VERSION 5.8 ;
BUSBITCHARS "[]" ;
DIVIDERCHAR "/" ;
UNITS
    DATABASE MICRONS 1000 ;
END UNITS

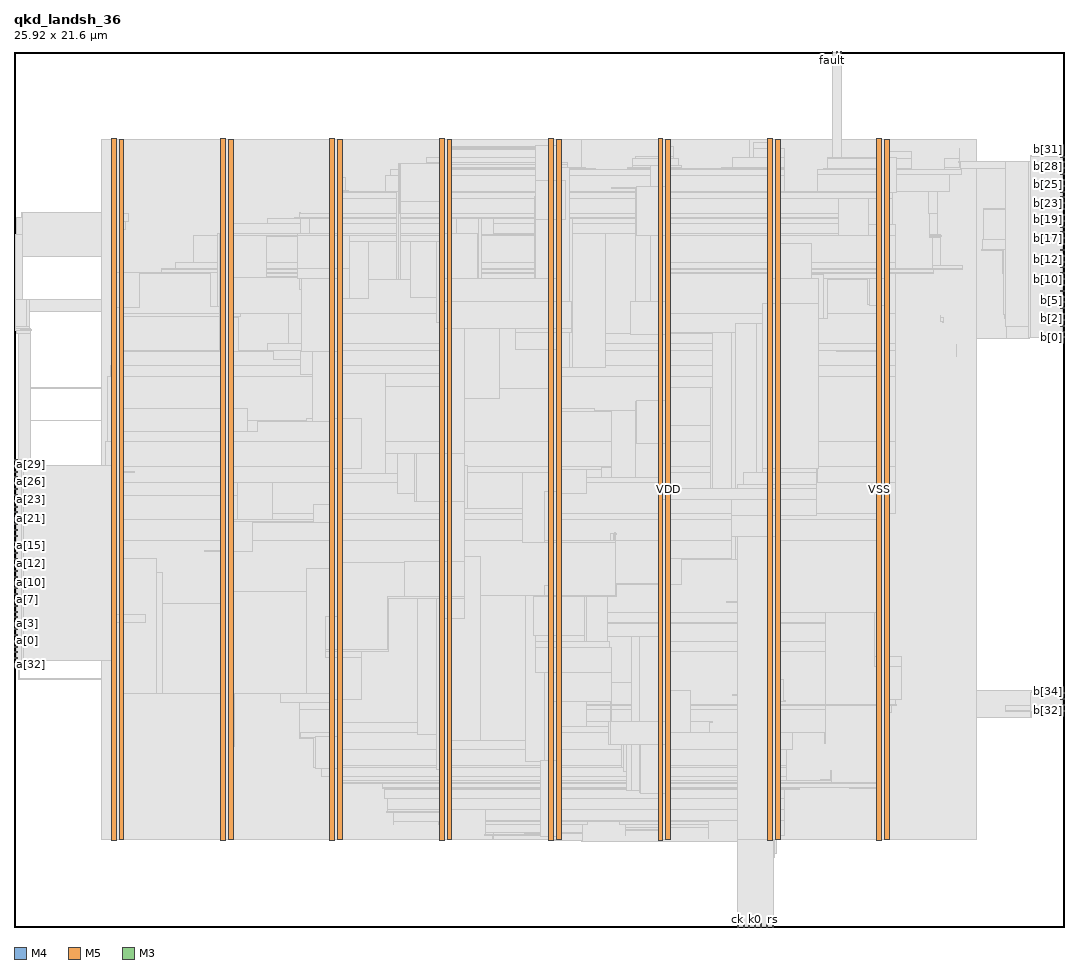
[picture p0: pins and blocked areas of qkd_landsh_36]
MACRO qkd_landsh_36
  FOREIGN qkd_landsh_36 0 0 ;
  CLASS BLOCK ;
  SIZE 25.92 BY 21.6 ;
  PIN a[0]
    DIRECTION INPUT ;
    USE SIGNAL ;
    PORT
      LAYER M4 ;
        RECT  0 7.056 0.084 7.08 ;
    END
  END a[0]
  PIN a[10]
    DIRECTION INPUT ;
    USE SIGNAL ;
    PORT
      LAYER M4 ;
        RECT  0 8.496 0.084 8.52 ;
    END
  END a[10]
  PIN a[11]
    DIRECTION INPUT ;
    USE SIGNAL ;
    PORT
      LAYER M4 ;
        RECT  0 8.64 0.084 8.664 ;
    END
  END a[11]
  PIN a[12]
    DIRECTION INPUT ;
    USE SIGNAL ;
    PORT
      LAYER M4 ;
        RECT  0 8.784 0.084 8.808 ;
    END
  END a[12]
  PIN a[13]
    DIRECTION INPUT ;
    USE SIGNAL ;
    PORT
      LAYER M4 ;
        RECT  0 8.928 0.084 8.952 ;
    END
  END a[13]
  PIN a[14]
    DIRECTION INPUT ;
    USE SIGNAL ;
    PORT
      LAYER M4 ;
        RECT  0 9.072 0.084 9.096 ;
    END
  END a[14]
  PIN a[15]
    DIRECTION INPUT ;
    USE SIGNAL ;
    PORT
      LAYER M4 ;
        RECT  0 9.216 0.084 9.24 ;
    END
  END a[15]
  PIN a[16]
    DIRECTION INPUT ;
    USE SIGNAL ;
    PORT
      LAYER M4 ;
        RECT  0 9.36 0.084 9.384 ;
    END
  END a[16]
  PIN a[17]
    DIRECTION INPUT ;
    USE SIGNAL ;
    PORT
      LAYER M4 ;
        RECT  0 9.504 0.084 9.528 ;
    END
  END a[17]
  PIN a[18]
    DIRECTION INPUT ;
    USE SIGNAL ;
    PORT
      LAYER M4 ;
        RECT  0 9.648 0.084 9.672 ;
    END
  END a[18]
  PIN a[19]
    DIRECTION INPUT ;
    USE SIGNAL ;
    PORT
      LAYER M4 ;
        RECT  0 9.792 0.084 9.816 ;
    END
  END a[19]
  PIN a[1]
    DIRECTION INPUT ;
    USE SIGNAL ;
    PORT
      LAYER M4 ;
        RECT  0 7.2 0.084 7.224 ;
    END
  END a[1]
  PIN a[20]
    DIRECTION INPUT ;
    USE SIGNAL ;
    PORT
      LAYER M4 ;
        RECT  0 9.936 0.084 9.96 ;
    END
  END a[20]
  PIN a[21]
    DIRECTION INPUT ;
    USE SIGNAL ;
    PORT
      LAYER M4 ;
        RECT  0 10.08 0.084 10.104 ;
    END
  END a[21]
  PIN a[22]
    DIRECTION INPUT ;
    USE SIGNAL ;
    PORT
      LAYER M4 ;
        RECT  0 10.224 0.084 10.248 ;
    END
  END a[22]
  PIN a[23]
    DIRECTION INPUT ;
    USE SIGNAL ;
    PORT
      LAYER M4 ;
        RECT  0 10.368 0.084 10.392 ;
    END
  END a[23]
  PIN a[24]
    DIRECTION INPUT ;
    USE SIGNAL ;
    PORT
      LAYER M4 ;
        RECT  0 10.512 0.084 10.536 ;
    END
  END a[24]
  PIN a[25]
    DIRECTION INPUT ;
    USE SIGNAL ;
    PORT
      LAYER M4 ;
        RECT  0 10.656 0.084 10.68 ;
    END
  END a[25]
  PIN a[26]
    DIRECTION INPUT ;
    USE SIGNAL ;
    PORT
      LAYER M4 ;
        RECT  0 10.8 0.084 10.824 ;
    END
  END a[26]
  PIN a[27]
    DIRECTION INPUT ;
    USE SIGNAL ;
    PORT
      LAYER M4 ;
        RECT  0 10.944 0.084 10.968 ;
    END
  END a[27]
  PIN a[28]
    DIRECTION INPUT ;
    USE SIGNAL ;
    PORT
      LAYER M4 ;
        RECT  0 11.088 0.084 11.112 ;
    END
  END a[28]
  PIN a[29]
    DIRECTION INPUT ;
    USE SIGNAL ;
    PORT
      LAYER M4 ;
        RECT  0 11.232 0.084 11.256 ;
    END
  END a[29]
  PIN a[2]
    DIRECTION INPUT ;
    USE SIGNAL ;
    PORT
      LAYER M4 ;
        RECT  0 7.344 0.084 7.368 ;
    END
  END a[2]
  PIN a[30]
    DIRECTION INPUT ;
    USE SIGNAL ;
    PORT
      LAYER M4 ;
        RECT  0 11.376 0.084 11.4 ;
    END
  END a[30]
  PIN a[31]
    DIRECTION INPUT ;
    USE SIGNAL ;
    PORT
      LAYER M4 ;
        RECT  0 11.52 0.084 11.544 ;
    END
  END a[31]
  PIN a[32]
    DIRECTION INPUT ;
    USE SIGNAL ;
    PORT
      LAYER M4 ;
        RECT  0 6.48 0.084 6.504 ;
    END
  END a[32]
  PIN a[33]
    DIRECTION INPUT ;
    USE SIGNAL ;
    PORT
      LAYER M4 ;
        RECT  0 6.624 0.084 6.648 ;
    END
  END a[33]
  PIN a[34]
    DIRECTION INPUT ;
    USE SIGNAL ;
    PORT
      LAYER M4 ;
        RECT  0 6.768 0.084 6.792 ;
    END
  END a[34]
  PIN a[35]
    DIRECTION INPUT ;
    USE SIGNAL ;
    PORT
      LAYER M4 ;
        RECT  0 6.912 0.084 6.936 ;
    END
  END a[35]
  PIN a[3]
    DIRECTION INPUT ;
    USE SIGNAL ;
    PORT
      LAYER M4 ;
        RECT  0 7.488 0.084 7.512 ;
    END
  END a[3]
  PIN a[4]
    DIRECTION INPUT ;
    USE SIGNAL ;
    PORT
      LAYER M4 ;
        RECT  0 7.632 0.084 7.656 ;
    END
  END a[4]
  PIN a[5]
    DIRECTION INPUT ;
    USE SIGNAL ;
    PORT
      LAYER M4 ;
        RECT  0 7.776 0.084 7.8 ;
    END
  END a[5]
  PIN a[6]
    DIRECTION INPUT ;
    USE SIGNAL ;
    PORT
      LAYER M4 ;
        RECT  0 7.92 0.084 7.944 ;
    END
  END a[6]
  PIN a[7]
    DIRECTION INPUT ;
    USE SIGNAL ;
    PORT
      LAYER M4 ;
        RECT  0 8.064 0.084 8.088 ;
    END
  END a[7]
  PIN a[8]
    DIRECTION INPUT ;
    USE SIGNAL ;
    PORT
      LAYER M4 ;
        RECT  0 8.208 0.084 8.232 ;
    END
  END a[8]
  PIN a[9]
    DIRECTION INPUT ;
    USE SIGNAL ;
    PORT
      LAYER M4 ;
        RECT  0 8.352 0.084 8.376 ;
    END
  END a[9]
  PIN b[0]
    DIRECTION OUTPUT ;
    USE SIGNAL ;
    PORT
      LAYER M4 ;
        RECT  25.836 14.544 25.92 14.568 ;
    END
  END b[0]
  PIN b[10]
    DIRECTION OUTPUT ;
    USE SIGNAL ;
    PORT
      LAYER M4 ;
        RECT  25.836 15.984 25.92 16.008 ;
    END
  END b[10]
  PIN b[11]
    DIRECTION OUTPUT ;
    USE SIGNAL ;
    PORT
      LAYER M4 ;
        RECT  25.836 16.128 25.92 16.152 ;
    END
  END b[11]
  PIN b[12]
    DIRECTION OUTPUT ;
    USE SIGNAL ;
    PORT
      LAYER M4 ;
        RECT  25.836 16.272 25.92 16.296 ;
    END
  END b[12]
  PIN b[13]
    DIRECTION OUTPUT ;
    USE SIGNAL ;
    PORT
      LAYER M4 ;
        RECT  25.836 16.416 25.92 16.44 ;
    END
  END b[13]
  PIN b[14]
    DIRECTION OUTPUT ;
    USE SIGNAL ;
    PORT
      LAYER M4 ;
        RECT  25.836 16.56 25.92 16.584 ;
    END
  END b[14]
  PIN b[15]
    DIRECTION OUTPUT ;
    USE SIGNAL ;
    PORT
      LAYER M4 ;
        RECT  25.836 16.704 25.92 16.728 ;
    END
  END b[15]
  PIN b[16]
    DIRECTION OUTPUT ;
    USE SIGNAL ;
    PORT
      LAYER M4 ;
        RECT  25.836 16.848 25.92 16.872 ;
    END
  END b[16]
  PIN b[17]
    DIRECTION OUTPUT ;
    USE SIGNAL ;
    PORT
      LAYER M4 ;
        RECT  25.836 16.992 25.92 17.016 ;
    END
  END b[17]
  PIN b[18]
    DIRECTION OUTPUT ;
    USE SIGNAL ;
    PORT
      LAYER M4 ;
        RECT  25.836 17.136 25.92 17.16 ;
    END
  END b[18]
  PIN b[19]
    DIRECTION OUTPUT ;
    USE SIGNAL ;
    PORT
      LAYER M4 ;
        RECT  25.836 17.28 25.92 17.304 ;
    END
  END b[19]
  PIN b[1]
    DIRECTION OUTPUT ;
    USE SIGNAL ;
    PORT
      LAYER M4 ;
        RECT  25.836 14.688 25.92 14.712 ;
    END
  END b[1]
  PIN b[20]
    DIRECTION OUTPUT ;
    USE SIGNAL ;
    PORT
      LAYER M4 ;
        RECT  25.836 17.424 25.92 17.448 ;
    END
  END b[20]
  PIN b[21]
    DIRECTION OUTPUT ;
    USE SIGNAL ;
    PORT
      LAYER M4 ;
        RECT  25.836 17.568 25.92 17.592 ;
    END
  END b[21]
  PIN b[22]
    DIRECTION OUTPUT ;
    USE SIGNAL ;
    PORT
      LAYER M4 ;
        RECT  25.836 17.712 25.92 17.736 ;
    END
  END b[22]
  PIN b[23]
    DIRECTION OUTPUT ;
    USE SIGNAL ;
    PORT
      LAYER M4 ;
        RECT  25.836 17.856 25.92 17.88 ;
    END
  END b[23]
  PIN b[24]
    DIRECTION OUTPUT ;
    USE SIGNAL ;
    PORT
      LAYER M4 ;
        RECT  25.836 18 25.92 18.024 ;
    END
  END b[24]
  PIN b[25]
    DIRECTION OUTPUT ;
    USE SIGNAL ;
    PORT
      LAYER M4 ;
        RECT  25.836 18.144 25.92 18.168 ;
    END
  END b[25]
  PIN b[26]
    DIRECTION OUTPUT ;
    USE SIGNAL ;
    PORT
      LAYER M4 ;
        RECT  25.836 18.288 25.92 18.312 ;
    END
  END b[26]
  PIN b[27]
    DIRECTION OUTPUT ;
    USE SIGNAL ;
    PORT
      LAYER M4 ;
        RECT  25.836 18.432 25.92 18.456 ;
    END
  END b[27]
  PIN b[28]
    DIRECTION OUTPUT ;
    USE SIGNAL ;
    PORT
      LAYER M4 ;
        RECT  25.836 18.576 25.92 18.6 ;
    END
  END b[28]
  PIN b[29]
    DIRECTION OUTPUT ;
    USE SIGNAL ;
    PORT
      LAYER M4 ;
        RECT  25.836 18.72 25.92 18.744 ;
    END
  END b[29]
  PIN b[2]
    DIRECTION OUTPUT ;
    USE SIGNAL ;
    PORT
      LAYER M4 ;
        RECT  25.836 14.832 25.92 14.856 ;
    END
  END b[2]
  PIN b[30]
    DIRECTION OUTPUT ;
    USE SIGNAL ;
    PORT
      LAYER M4 ;
        RECT  25.836 18.864 25.92 18.888 ;
    END
  END b[30]
  PIN b[31]
    DIRECTION OUTPUT ;
    USE SIGNAL ;
    PORT
      LAYER M4 ;
        RECT  25.836 19.008 25.92 19.032 ;
    END
  END b[31]
  PIN b[32]
    DIRECTION OUTPUT ;
    USE SIGNAL ;
    PORT
      LAYER M4 ;
        RECT  25.836 5.328 25.92 5.352 ;
    END
  END b[32]
  PIN b[33]
    DIRECTION OUTPUT ;
    USE SIGNAL ;
    PORT
      LAYER M4 ;
        RECT  25.836 5.472 25.92 5.496 ;
    END
  END b[33]
  PIN b[34]
    DIRECTION OUTPUT ;
    USE SIGNAL ;
    PORT
      LAYER M4 ;
        RECT  25.836 5.616 25.92 5.64 ;
    END
  END b[34]
  PIN b[35]
    DIRECTION OUTPUT ;
    USE SIGNAL ;
    PORT
      LAYER M4 ;
        RECT  25.836 5.76 25.92 5.784 ;
    END
  END b[35]
  PIN b[3]
    DIRECTION OUTPUT ;
    USE SIGNAL ;
    PORT
      LAYER M4 ;
        RECT  25.836 14.976 25.92 15 ;
    END
  END b[3]
  PIN b[4]
    DIRECTION OUTPUT ;
    USE SIGNAL ;
    PORT
      LAYER M4 ;
        RECT  25.836 15.12 25.92 15.144 ;
    END
  END b[4]
  PIN b[5]
    DIRECTION OUTPUT ;
    USE SIGNAL ;
    PORT
      LAYER M4 ;
        RECT  25.836 15.264 25.92 15.288 ;
    END
  END b[5]
  PIN b[6]
    DIRECTION OUTPUT ;
    USE SIGNAL ;
    PORT
      LAYER M4 ;
        RECT  25.836 15.408 25.92 15.432 ;
    END
  END b[6]
  PIN b[7]
    DIRECTION OUTPUT ;
    USE SIGNAL ;
    PORT
      LAYER M4 ;
        RECT  25.836 15.552 25.92 15.576 ;
    END
  END b[7]
  PIN b[8]
    DIRECTION OUTPUT ;
    USE SIGNAL ;
    PORT
      LAYER M4 ;
        RECT  25.836 15.696 25.92 15.72 ;
    END
  END b[8]
  PIN b[9]
    DIRECTION OUTPUT ;
    USE SIGNAL ;
    PORT
      LAYER M4 ;
        RECT  25.836 15.84 25.92 15.864 ;
    END
  END b[9]
  PIN ck
    DIRECTION INPUT ;
    USE SIGNAL ;
    PORT
      LAYER M5 ;
        RECT  17.856 0 17.88 0.084 ;
    END
  END ck
  PIN ckf
    DIRECTION INPUT ;
    USE SIGNAL ;
    PORT
      LAYER M5 ;
        RECT  18 0 18.024 0.084 ;
    END
  END ckf
  PIN ea
    DIRECTION INPUT ;
    USE SIGNAL ;
    PORT
      LAYER M5 ;
        RECT  18.144 0 18.168 0.084 ;
    END
  END ea
  PIN fault
    DIRECTION OUTPUT ;
    USE SIGNAL ;
    PORT
      LAYER M3 ;
        RECT  20.196 21.563 20.214 21.6 ;
    END
  END fault
  PIN k0
    DIRECTION INPUT ;
    USE SIGNAL ;
    PORT
      LAYER M5 ;
        RECT  18.288 0 18.312 0.084 ;
    END
  END k0
  PIN k1
    DIRECTION INPUT ;
    USE SIGNAL ;
    PORT
      LAYER M5 ;
        RECT  18.432 0 18.456 0.084 ;
    END
  END k1
  PIN k2
    DIRECTION INPUT ;
    USE SIGNAL ;
    PORT
      LAYER M5 ;
        RECT  18.576 0 18.6 0.084 ;
    END
  END k2
  PIN rs
    DIRECTION INPUT ;
    USE SIGNAL ;
    PORT
      LAYER M5 ;
        RECT  18.72 0 18.744 0.084 ;
    END
  END rs
  PIN tie_hi
    DIRECTION OUTPUT ;
    USE SIGNAL ;
    PORT
      LAYER M3 ;
        RECT  20.304 21.563 20.322 21.6 ;
    END
  END tie_hi
  PIN tie_lo
    DIRECTION OUTPUT ;
    USE SIGNAL ;
    PORT
      LAYER M3 ;
        RECT  20.412 21.563 20.43 21.6 ;
    END
  END tie_lo
  PIN VDD
    DIRECTION INOUT ;
    USE POWER ;
    PORT
      LAYER M5 ;
        RECT  21.492 2.151 21.612 19.449 ;
        RECT  18.792 2.151 18.912 19.449 ;
        RECT  16.092 2.151 16.212 19.449 ;
        RECT  13.392 2.151 13.512 19.449 ;
        RECT  10.692 2.151 10.812 19.449 ;
        RECT  7.992 2.151 8.112 19.449 ;
        RECT  5.292 2.151 5.412 19.449 ;
        RECT  2.592 2.151 2.712 19.449 ;
    END
  END VDD
  PIN VSS
    DIRECTION INOUT ;
    USE GROUND ;
    PORT
      LAYER M5 ;
        RECT  21.3 2.137 21.42 19.463 ;
        RECT  18.6 2.137 18.72 19.463 ;
        RECT  15.9 2.137 16.02 19.463 ;
        RECT  13.2 2.137 13.32 19.463 ;
        RECT  10.5 2.137 10.62 19.463 ;
        RECT  7.8 2.137 7.92 19.463 ;
        RECT  5.1 2.137 5.22 19.463 ;
        RECT  2.4 2.137 2.52 19.463 ;
    END
  END VSS
  OBS
    LAYER RVTN ;
     RECT  2.16 2.16 23.76 2.295 ;
     RECT  2.16 2.565 23.76 2.835 ;
     RECT  2.16 3.105 23.76 3.375 ;
     RECT  2.16 3.645 23.76 3.915 ;
     RECT  2.16 4.185 23.76 4.455 ;
     RECT  2.16 4.725 23.76 4.995 ;
     RECT  2.16 5.265 23.76 5.535 ;
     RECT  2.16 5.805 23.76 6.075 ;
     RECT  2.16 6.345 23.76 6.615 ;
     RECT  2.16 6.885 23.76 7.155 ;
     RECT  2.16 7.425 23.76 7.695 ;
     RECT  2.16 7.965 23.76 8.235 ;
     RECT  2.16 8.505 23.76 8.775 ;
     RECT  2.16 9.045 23.76 9.315 ;
     RECT  2.16 9.585 23.76 9.855 ;
     RECT  2.16 10.125 23.76 10.395 ;
     RECT  2.16 10.665 23.76 10.935 ;
     RECT  2.16 11.205 23.76 11.475 ;
     RECT  2.16 11.745 23.76 12.015 ;
     RECT  2.16 12.285 23.76 12.555 ;
     RECT  2.16 12.825 23.76 13.095 ;
     RECT  2.16 13.365 23.76 13.635 ;
     RECT  2.16 13.905 23.76 14.175 ;
     RECT  2.16 14.445 23.76 14.715 ;
     RECT  2.16 14.985 23.76 15.255 ;
     RECT  2.16 15.525 23.76 15.795 ;
     RECT  2.16 16.065 23.76 16.335 ;
     RECT  2.16 16.605 23.76 16.875 ;
     RECT  2.16 17.145 23.76 17.415 ;
     RECT  2.16 17.685 23.76 17.955 ;
     RECT  2.16 18.225 23.76 18.495 ;
     RECT  2.16 18.765 23.76 19.035 ;
     RECT  2.16 19.305 23.76 19.44 ;
    LAYER RVTP ;
     RECT  2.16 2.295 23.76 2.565 ;
     RECT  2.16 2.835 23.76 3.105 ;
     RECT  2.16 3.375 23.76 3.645 ;
     RECT  2.16 3.915 23.76 4.185 ;
     RECT  2.16 4.455 23.76 4.725 ;
     RECT  2.16 4.995 23.76 5.265 ;
     RECT  2.16 5.535 23.76 5.805 ;
     RECT  2.16 6.075 23.76 6.345 ;
     RECT  2.16 6.615 23.76 6.885 ;
     RECT  2.16 7.155 23.76 7.425 ;
     RECT  2.16 7.695 23.76 7.965 ;
     RECT  2.16 8.235 23.76 8.505 ;
     RECT  2.16 8.775 23.76 9.045 ;
     RECT  2.16 9.315 23.76 9.585 ;
     RECT  2.16 9.855 23.76 10.125 ;
     RECT  2.16 10.395 23.76 10.665 ;
     RECT  2.16 10.935 23.76 11.205 ;
     RECT  2.16 11.475 23.76 11.745 ;
     RECT  2.16 12.015 23.76 12.285 ;
     RECT  2.16 12.555 23.76 12.825 ;
     RECT  2.16 13.095 23.76 13.365 ;
     RECT  2.16 13.635 23.76 13.905 ;
     RECT  2.16 14.175 23.76 14.445 ;
     RECT  2.16 14.715 23.76 14.985 ;
     RECT  2.16 15.255 23.76 15.525 ;
     RECT  2.16 15.795 23.76 16.065 ;
     RECT  2.16 16.335 23.76 16.605 ;
     RECT  2.16 16.875 23.76 17.145 ;
     RECT  2.16 17.415 23.76 17.685 ;
     RECT  2.16 17.955 23.76 18.225 ;
     RECT  2.16 18.495 23.76 18.765 ;
     RECT  2.16 19.035 23.76 19.305 ;
    LAYER M1 ;
     RECT  2.16 2.151 23.76 19.449 ;
    LAYER M2 ;
     RECT  0.031 14.724 0.067 14.742 ;
     RECT  0.031 17.082 0.067 17.1 ;
     RECT  0.067 14.652 0.103 14.742 ;
     RECT  0.067 17.082 0.139 17.514 ;
     RECT  0.139 16.542 0.175 17.514 ;
     RECT  0.103 14.652 0.203 15.21 ;
     RECT  0.103 8.856 0.211 8.874 ;
     RECT  0.211 8.442 0.239 8.874 ;
     RECT  0.203 14.76 0.283 15.21 ;
     RECT  0.283 14.76 0.311 15.48 ;
     RECT  0.211 10.836 0.347 10.854 ;
     RECT  0.311 14.796 0.383 15.48 ;
     RECT  0.103 6.12 2.16 6.138 ;
     RECT  0.535 7.398 2.16 7.416 ;
     RECT  0.239 8.442 2.16 8.496 ;
     RECT  0.319 12.492 2.16 12.51 ;
     RECT  0.247 13.302 2.16 13.32 ;
     RECT  0.383 15.192 2.16 15.48 ;
     RECT  0.175 16.542 2.16 17.64 ;
     RECT  2.16 2.151 13.999 19.449 ;
     RECT  13.999 2.106 18.167 19.449 ;
     RECT  18.167 2.151 23.76 19.449 ;
     RECT  23.76 14.526 24.503 18.864 ;
     RECT  24.503 14.526 25.079 16.434 ;
     RECT  24.503 17.388 25.079 18.864 ;
     RECT  23.76 5.166 25.115 5.832 ;
     RECT  25.079 14.652 25.115 14.67 ;
     RECT  25.079 15.426 25.115 16.434 ;
     RECT  25.079 17.424 25.115 18.864 ;
     RECT  25.115 5.814 25.835 5.832 ;
     RECT  25.115 15.426 25.835 16.164 ;
     RECT  25.115 17.424 25.835 17.64 ;
    LAYER M3 ;
     RECT  18.144 0.091 18.162 0.571 ;
     RECT  18.144 0.571 18.306 1.723 ;
     RECT  18.144 1.723 18.774 1.819 ;
     RECT  14.004 2.101 14.022 2.143 ;
     RECT  11.808 2.191 11.826 2.251 ;
     RECT  18.144 1.819 18.81 2.263 ;
     RECT  13.215 2.143 14.022 2.299 ;
     RECT  11.628 2.251 11.826 2.335 ;
     RECT  12.6 2.299 14.022 2.335 ;
     RECT  15.084 2.263 15.102 2.371 ;
     RECT  15.915 2.143 16.005 2.371 ;
     RECT  2.415 2.143 2.505 2.413 ;
     RECT  5.115 2.143 5.205 2.413 ;
     RECT  7.815 2.143 7.905 2.413 ;
     RECT  10.515 2.143 10.605 2.413 ;
     RECT  15.084 2.371 16.005 2.413 ;
     RECT  21.315 2.143 21.405 2.413 ;
     RECT  15.084 2.413 16.197 2.461 ;
     RECT  17.136 2.191 17.154 2.461 ;
     RECT  10.515 2.413 10.797 2.533 ;
     RECT  11.628 2.335 14.022 2.533 ;
     RECT  15.084 2.461 17.154 2.533 ;
     RECT  9.36 2.533 9.378 2.605 ;
     RECT  10.476 2.533 10.797 2.605 ;
     RECT  11.628 2.533 14.166 2.605 ;
     RECT  14.94 2.533 17.154 2.605 ;
     RECT  11.628 2.605 17.154 2.641 ;
     RECT  18.144 2.263 19.026 2.641 ;
     RECT  9.36 2.605 10.797 2.827 ;
     RECT  9.216 2.827 10.797 2.911 ;
     RECT  11.628 2.641 19.026 2.911 ;
     RECT  9.216 2.911 19.026 3.181 ;
     RECT  9.144 3.181 19.026 3.403 ;
     RECT  9.144 3.403 19.386 3.415 ;
     RECT  21.315 2.413 21.597 3.415 ;
     RECT  9.108 3.415 19.386 3.451 ;
     RECT  20.628 3.415 21.597 3.451 ;
     RECT  7.815 2.413 8.097 3.541 ;
     RECT  9.108 3.451 21.597 3.541 ;
     RECT  7.815 3.541 21.597 3.569 ;
     RECT  7.815 3.569 20.178 3.605 ;
     RECT  19.908 3.605 20.178 3.641 ;
     RECT  7.815 3.605 19.062 3.721 ;
     RECT  20.16 3.641 20.178 3.875 ;
     RECT  7.596 3.721 19.062 3.931 ;
     RECT  7.416 3.931 19.062 3.983 ;
     RECT  7.815 3.983 19.062 4.387 ;
     RECT  5.115 2.413 5.397 4.459 ;
     RECT  7.056 4.651 7.074 4.801 ;
     RECT  7.815 4.387 19.206 4.801 ;
     RECT  20.016 4.531 20.034 4.801 ;
     RECT  21.315 3.569 21.597 5.305 ;
     RECT  25.092 5.161 25.11 5.323 ;
     RECT  7.056 4.801 20.034 5.369 ;
     RECT  24.48 5.323 25.11 5.459 ;
     RECT  9.108 5.369 20.034 5.461 ;
     RECT  21.315 5.305 21.654 5.467 ;
     RECT  9.108 5.461 20.502 5.501 ;
     RECT  7.056 5.369 8.37 5.539 ;
     RECT  21.315 5.467 21.762 5.611 ;
     RECT  25.092 5.459 25.11 5.611 ;
     RECT  25.092 5.611 25.83 5.789 ;
     RECT  25.812 5.789 25.83 5.837 ;
     RECT  5.115 4.459 5.454 5.845 ;
     RECT  5.115 5.845 5.778 5.881 ;
     RECT  6.588 5.539 8.37 5.881 ;
     RECT  3.564 5.755 3.582 6.115 ;
     RECT  5.115 5.881 8.37 6.179 ;
     RECT  3.564 6.115 3.942 6.241 ;
     RECT  21.315 5.611 21.906 6.421 ;
     RECT  0.108 6.115 0.126 6.475 ;
     RECT  3.564 6.241 3.978 6.547 ;
     RECT  5.115 6.179 8.19 6.547 ;
     RECT  2.415 2.413 2.697 6.583 ;
     RECT  3.564 6.547 8.19 6.583 ;
     RECT  0.108 6.475 0.162 6.605 ;
     RECT  21.24 6.421 21.906 6.683 ;
     RECT  9.108 5.501 20.034 6.808 ;
     RECT  0.108 6.605 0.126 6.941 ;
     RECT  2.415 6.583 8.19 7.051 ;
     RECT  9.036 6.808 20.034 7.051 ;
     RECT  2.304 7.051 20.034 7.483 ;
     RECT  2.268 7.483 20.034 7.529 ;
     RECT  2.304 7.529 20.034 7.771 ;
     RECT  21.24 6.683 21.597 7.771 ;
     RECT  0.54 7.393 0.558 8.059 ;
     RECT  0.108 8.059 0.558 8.237 ;
     RECT  0.108 8.237 0.27 8.879 ;
     RECT  2.304 7.771 21.597 9.545 ;
     RECT  0.144 8.879 0.27 9.787 ;
     RECT  2.376 9.545 21.597 10.049 ;
     RECT  6.372 10.049 21.597 10.201 ;
     RECT  0.108 9.787 0.27 10.363 ;
     RECT  2.376 10.049 5.526 10.651 ;
     RECT  0.108 10.363 0.378 10.939 ;
     RECT  2.304 10.651 5.526 10.975 ;
     RECT  6.372 10.201 21.762 10.975 ;
     RECT  2.304 10.975 21.762 11.371 ;
     RECT  2.268 11.371 21.762 11.975 ;
     RECT  2.304 11.975 21.762 13.595 ;
     RECT  2.376 13.595 21.762 13.865 ;
     RECT  2.415 13.865 21.762 14.243 ;
     RECT  23.256 14.071 23.274 14.369 ;
     RECT  6.264 14.243 21.762 14.405 ;
     RECT  0.108 10.939 0.414 14.647 ;
     RECT  25.056 14.521 25.074 14.647 ;
     RECT  25.056 14.647 25.11 14.717 ;
     RECT  0.072 14.647 0.414 14.719 ;
     RECT  0.036 14.719 0.414 14.765 ;
     RECT  0.036 14.765 0.378 14.819 ;
     RECT  25.056 14.717 25.074 14.827 ;
     RECT  22.932 14.917 22.95 14.953 ;
     RECT  24.48 14.827 25.074 15.025 ;
     RECT  22.86 14.953 22.95 15.053 ;
     RECT  2.415 14.243 5.526 15.061 ;
     RECT  22.86 15.053 22.878 15.089 ;
     RECT  2.415 15.061 5.598 15.151 ;
     RECT  6.768 14.405 21.762 15.151 ;
     RECT  0.036 14.819 0.306 15.485 ;
     RECT  24.444 15.025 25.074 15.961 ;
     RECT  25.812 15.403 25.83 15.961 ;
     RECT  24.444 15.961 25.83 16.123 ;
     RECT  2.415 15.151 21.762 16.141 ;
     RECT  2.415 16.141 22.698 16.169 ;
     RECT  24.408 16.123 25.83 16.169 ;
     RECT  3.636 16.169 22.698 16.231 ;
     RECT  3.636 16.231 23.418 16.259 ;
     RECT  22.68 16.259 23.418 16.331 ;
     RECT  3.996 16.259 21.762 16.403 ;
     RECT  24.408 16.169 25.11 16.589 ;
     RECT  24.408 16.589 25.074 16.699 ;
     RECT  23.904 16.699 25.074 16.979 ;
     RECT  22.68 16.331 22.878 17.032 ;
     RECT  4.428 16.403 21.762 17.069 ;
     RECT  0.036 15.485 0.198 17.105 ;
     RECT  22.608 17.032 22.878 17.105 ;
     RECT  5.04 17.069 20.358 17.117 ;
     RECT  2.415 16.169 2.697 17.221 ;
     RECT  21.096 17.069 21.762 17.339 ;
     RECT  5.115 17.117 20.358 17.375 ;
     RECT  2.415 17.221 2.754 17.419 ;
     RECT  6.264 17.375 20.358 17.483 ;
     RECT  0.072 17.105 0.198 17.519 ;
     RECT  6.912 17.483 20.358 17.519 ;
     RECT  2.415 17.419 2.826 17.609 ;
     RECT  7.056 17.519 20.358 17.609 ;
     RECT  22.608 17.105 22.806 17.617 ;
     RECT  0.18 17.519 0.198 17.645 ;
     RECT  7.056 17.609 7.074 17.645 ;
     RECT  25.812 17.131 25.83 17.645 ;
     RECT  23.94 16.979 25.074 17.741 ;
     RECT  7.815 17.609 20.358 17.995 ;
     RECT  21.096 17.339 21.69 17.995 ;
     RECT  7.815 17.995 21.69 18.139 ;
     RECT  7.815 18.139 21.762 18.149 ;
     RECT  19.836 18.149 21.762 18.157 ;
     RECT  22.572 17.617 22.806 18.157 ;
     RECT  7.815 18.149 8.262 18.185 ;
     RECT  24.48 17.741 25.074 18.221 ;
     RECT  25.056 18.221 25.074 18.301 ;
     RECT  7.815 18.185 8.19 18.491 ;
     RECT  9.18 18.149 19.026 18.563 ;
     RECT  19.836 18.157 23.094 18.571 ;
     RECT  9.288 18.563 19.026 18.689 ;
     RECT  19.836 18.571 23.382 18.689 ;
     RECT  25.056 18.301 25.11 18.689 ;
     RECT  10.008 18.689 14.346 18.725 ;
     RECT  15.156 18.689 19.026 18.725 ;
     RECT  19.98 18.689 22.158 18.725 ;
     RECT  22.968 18.689 23.382 18.749 ;
     RECT  10.116 18.725 14.094 18.761 ;
     RECT  15.156 18.725 16.47 18.761 ;
     RECT  17.46 18.725 19.026 18.761 ;
     RECT  15.264 18.761 16.47 18.797 ;
     RECT  10.116 18.761 13.662 18.833 ;
     RECT  10.188 18.833 13.662 18.869 ;
     RECT  15.264 18.797 16.398 18.959 ;
     RECT  20.088 18.725 22.158 18.959 ;
     RECT  22.968 18.749 23.346 18.959 ;
     RECT  10.188 18.869 13.497 18.995 ;
     RECT  17.748 18.761 19.026 18.995 ;
     RECT  20.088 18.959 20.466 18.995 ;
     RECT  15.336 18.959 16.29 19.031 ;
     RECT  25.092 18.689 25.11 19.037 ;
     RECT  21.315 18.959 22.158 19.139 ;
     RECT  2.415 17.609 2.697 19.187 ;
     RECT  5.115 17.375 5.397 19.187 ;
     RECT  7.815 18.491 8.097 19.187 ;
     RECT  10.515 18.995 13.497 19.187 ;
     RECT  21.315 19.139 21.597 19.187 ;
     RECT  10.515 19.187 13.305 19.229 ;
     RECT  18.252 18.995 19.026 19.229 ;
     RECT  23.328 18.959 23.346 19.229 ;
     RECT  12.06 19.229 13.305 19.265 ;
     RECT  15.915 19.031 16.29 19.265 ;
     RECT  12.096 19.265 12.114 19.277 ;
     RECT  18.252 19.229 18.705 19.373 ;
     RECT  2.415 19.187 2.505 19.457 ;
     RECT  5.115 19.187 5.205 19.457 ;
     RECT  7.815 19.187 7.905 19.457 ;
     RECT  10.515 19.229 10.605 19.457 ;
     RECT  13.215 19.265 13.305 19.457 ;
     RECT  15.915 19.265 16.005 19.457 ;
     RECT  18.615 19.373 18.705 19.457 ;
     RECT  21.315 19.187 21.405 19.457 ;
     RECT  20.196 18.995 20.43 21.581 ;
    LAYER M4 ;
     RECT  0.06 6.48 0.173 11.544 ;
     RECT  0.173 6.576 0.245 11.544 ;
     RECT  0.169 14.736 0.425 14.76 ;
     RECT  0.245 6.576 2.408 11.4 ;
     RECT  2.408 2.148 2.512 19.452 ;
     RECT  2.512 2.418 2.704 19.182 ;
     RECT  2.704 11.232 2.981 11.256 ;
     RECT  2.704 15.312 3.107 16.152 ;
     RECT  2.704 5.76 3.521 9.096 ;
     RECT  3.521 5.76 3.665 8.76 ;
     RECT  3.107 16.128 4.849 16.152 ;
     RECT  4.849 15.312 5.029 16.152 ;
     RECT  2.704 14.208 5.065 14.232 ;
     RECT  5.029 15.312 5.065 17.112 ;
     RECT  3.665 5.76 5.101 7.992 ;
     RECT  5.101 5.76 5.108 8.28 ;
     RECT  4.705 9.264 5.108 9.288 ;
     RECT  2.704 12.24 5.108 12.792 ;
     RECT  5.065 14.208 5.108 17.112 ;
     RECT  5.108 2.148 5.212 19.452 ;
     RECT  5.212 2.418 5.404 19.182 ;
     RECT  5.404 14.208 5.537 15.048 ;
     RECT  5.404 12.24 5.753 12.792 ;
     RECT  5.404 9.264 5.897 10.008 ;
     RECT  5.753 12.24 6.005 12.504 ;
     RECT  5.404 16.032 6.221 17.064 ;
     RECT  5.537 14.208 6.397 14.232 ;
     RECT  6.221 17.04 6.997 17.064 ;
     RECT  6.221 16.032 7.052 16.056 ;
     RECT  6.397 14.016 7.081 14.232 ;
     RECT  6.997 17.04 7.081 17.112 ;
     RECT  7.052 15.744 7.153 16.056 ;
     RECT  5.404 5.76 7.225 8.28 ;
     RECT  6.005 12.48 7.225 12.504 ;
     RECT  7.153 15.504 7.297 16.056 ;
     RECT  7.081 17.04 7.297 17.496 ;
     RECT  7.225 12.48 7.369 12.552 ;
     RECT  7.081 13.632 7.369 14.232 ;
     RECT  7.045 4.656 7.405 4.68 ;
     RECT  5.897 9.984 7.405 10.008 ;
     RECT  7.405 3.936 7.808 4.68 ;
     RECT  7.225 5.76 7.808 8.856 ;
     RECT  7.405 9.984 7.808 10.44 ;
     RECT  7.369 12.48 7.808 14.232 ;
     RECT  7.297 15.504 7.808 17.496 ;
     RECT  7.808 2.148 7.912 19.452 ;
     RECT  7.912 2.418 8.104 19.182 ;
     RECT  8.104 15.504 8.291 17.064 ;
     RECT  8.291 15.504 8.741 16.92 ;
     RECT  8.104 11.184 9.173 13.656 ;
     RECT  8.741 15.984 9.452 16.92 ;
     RECT  8.104 18.144 9.452 18.168 ;
     RECT  9.173 11.184 9.457 11.688 ;
     RECT  9.452 15.984 9.493 18.168 ;
     RECT  9.493 15.984 9.539 18.84 ;
     RECT  9.539 15.984 9.781 16.92 ;
     RECT  9.457 10.704 9.884 11.688 ;
     RECT  8.104 5.04 9.961 9 ;
     RECT  9.961 4.752 10.429 9 ;
     RECT  9.781 15.552 10.429 16.92 ;
     RECT  10.429 14.928 10.501 16.92 ;
     RECT  9.539 17.904 10.501 18.84 ;
     RECT  9.205 2.832 10.508 2.856 ;
     RECT  10.429 3.888 10.508 9 ;
     RECT  9.884 10.512 10.508 11.688 ;
     RECT  9.173 13.344 10.508 13.656 ;
     RECT  10.501 14.928 10.508 18.84 ;
     RECT  10.508 2.148 10.612 19.452 ;
     RECT  10.612 2.418 10.804 19.272 ;
     RECT  10.804 13.056 10.931 17.496 ;
     RECT  10.804 10.32 11.189 11.4 ;
     RECT  10.931 15.888 11.459 17.496 ;
     RECT  10.804 4.608 11.513 9.144 ;
     RECT  11.459 15.984 11.549 17.496 ;
     RECT  11.549 17.088 11.837 17.496 ;
     RECT  10.931 13.056 11.981 14.808 ;
     RECT  11.189 10.32 12.553 11.208 ;
     RECT  11.513 4.608 12.625 8.184 ;
     RECT  11.549 15.984 12.853 16.008 ;
     RECT  11.837 17.088 12.853 17.112 ;
     RECT  12.853 15.984 12.949 18.024 ;
     RECT  11.617 2.256 12.997 2.28 ;
     RECT  12.625 4.08 13.093 8.184 ;
     RECT  12.997 2.256 13.208 3.048 ;
     RECT  13.093 4.08 13.208 8.424 ;
     RECT  12.553 9.504 13.208 11.208 ;
     RECT  11.981 13.296 13.208 14.808 ;
     RECT  12.949 15.984 13.208 18.216 ;
     RECT  10.804 19.248 13.208 19.272 ;
     RECT  13.208 2.148 13.312 19.452 ;
     RECT  13.312 2.418 13.504 19.182 ;
     RECT  13.504 13.824 13.709 18.744 ;
     RECT  13.709 13.824 13.781 17.496 ;
     RECT  13.709 18.72 14.105 18.744 ;
     RECT  13.504 4.944 14.14 9.528 ;
     RECT  13.504 10.704 14.141 11.304 ;
     RECT  13.504 12.72 14.321 12.792 ;
     RECT  14.141 11.088 14.497 11.304 ;
     RECT  13.781 13.824 14.609 17.112 ;
     RECT  14.14 6.048 14.645 9.528 ;
     RECT  14.14 4.944 14.684 5.064 ;
     RECT  14.645 8.16 14.713 9.528 ;
     RECT  14.497 11.088 14.749 11.352 ;
     RECT  14.321 12.72 14.749 12.744 ;
     RECT  14.713 8.16 14.789 9.72 ;
     RECT  14.789 8.16 14.867 8.472 ;
     RECT  14.789 9.696 14.867 9.72 ;
     RECT  14.684 4.512 15.001 5.064 ;
     RECT  15.001 3.936 15.037 5.064 ;
     RECT  15.037 3.84 15.109 5.064 ;
     RECT  15.109 3.36 15.253 5.064 ;
     RECT  14.645 6.048 15.253 7.176 ;
     RECT  14.749 11.088 15.349 12.744 ;
     RECT  14.609 14.64 15.349 17.112 ;
     RECT  14.749 18.24 15.349 18.264 ;
     RECT  15.253 3.36 15.445 7.176 ;
     RECT  15.349 14.64 15.721 18.264 ;
     RECT  15.445 3.312 15.908 7.176 ;
     RECT  14.867 8.448 15.908 8.472 ;
     RECT  15.349 11.088 15.908 12.984 ;
     RECT  15.721 14.64 15.908 18.792 ;
     RECT  15.908 2.148 16.012 19.452 ;
     RECT  16.012 2.418 16.204 19.182 ;
     RECT  16.204 8.448 16.481 9.096 ;
     RECT  16.204 4.8 16.697 5.832 ;
     RECT  16.697 4.8 17.165 5.064 ;
     RECT  16.204 10.56 17.197 11.208 ;
     RECT  16.204 12.384 17.197 13.32 ;
     RECT  17.197 10.56 17.233 13.32 ;
     RECT  16.204 14.64 17.233 14.664 ;
     RECT  17.165 5.04 17.237 5.064 ;
     RECT  16.481 9.072 17.701 9.096 ;
     RECT  17.233 10.56 17.701 14.664 ;
     RECT  17.701 9.072 17.809 14.664 ;
     RECT  17.737 5.712 18.025 5.736 ;
     RECT  18.133 0.096 18.217 0.12 ;
     RECT  18.205 1.104 18.277 1.128 ;
     RECT  17.593 8.016 18.325 8.04 ;
     RECT  17.809 9.072 18.325 14.904 ;
     RECT  18.277 0.576 18.361 1.128 ;
     RECT  18.025 5.712 18.38 6.12 ;
     RECT  18.361 1.104 18.467 1.128 ;
     RECT  17.881 2.832 18.469 2.856 ;
     RECT  18.385 4.656 18.469 4.68 ;
     RECT  18.38 5.712 18.469 6.84 ;
     RECT  18.325 8.016 18.469 14.904 ;
     RECT  18.565 1.728 18.608 1.752 ;
     RECT  18.469 2.832 18.608 3.432 ;
     RECT  18.469 4.656 18.608 6.84 ;
     RECT  18.469 8.016 18.608 15.384 ;
     RECT  18.608 1.728 18.712 19.452 ;
     RECT  18.712 1.728 18.785 19.182 ;
     RECT  18.785 1.824 18.821 19.182 ;
     RECT  18.821 2.418 18.904 19.182 ;
     RECT  18.904 5.568 19.001 6.12 ;
     RECT  19.001 5.568 19.037 5.592 ;
     RECT  18.904 3.408 19.397 3.432 ;
     RECT  18.904 10.176 19.505 11.832 ;
     RECT  18.904 15.024 19.685 16.872 ;
     RECT  19.505 10.176 19.811 11.352 ;
     RECT  19.811 10.992 19.829 11.352 ;
     RECT  19.829 11.328 19.859 11.352 ;
     RECT  19.685 15.024 19.973 16.104 ;
     RECT  19.973 15.024 20.081 16.008 ;
     RECT  20.081 15.984 21.077 16.008 ;
     RECT  20.473 5.472 21.308 5.496 ;
     RECT  20.293 14.208 21.308 14.232 ;
     RECT  21.077 15.36 21.308 16.008 ;
     RECT  20.437 18.96 21.308 18.984 ;
     RECT  21.308 2.148 21.412 19.452 ;
     RECT  21.412 2.418 21.604 19.182 ;
     RECT  21.604 5.472 21.773 5.496 ;
     RECT  21.604 18.144 21.773 18.984 ;
     RECT  22.597 17.04 22.889 17.064 ;
     RECT  23.317 18.864 23.353 18.888 ;
     RECT  23.893 16.704 24.397 16.728 ;
     RECT  24.397 16.128 24.433 16.728 ;
     RECT  24.433 15.12 24.469 16.728 ;
     RECT  23.929 17.712 24.469 17.736 ;
     RECT  23.353 18.72 24.469 18.888 ;
     RECT  24.469 14.832 25.045 18.888 ;
     RECT  24.469 5.328 25.081 5.352 ;
     RECT  25.045 14.544 25.081 18.888 ;
     RECT  25.081 5.328 25.884 5.784 ;
     RECT  25.081 14.544 25.884 19.032 ;
    LAYER M5 ;
     RECT  2.4 2.137 2.52 2.151 ;
     RECT  5.1 2.137 5.22 2.151 ;
     RECT  7.8 2.137 7.92 2.151 ;
     RECT  10.5 2.137 10.62 2.151 ;
     RECT  13.2 2.137 13.32 2.151 ;
     RECT  15.9 2.137 16.02 2.151 ;
     RECT  17.856 0.016 18.744 2.151 ;
     RECT  21.3 2.137 21.42 2.151 ;
     RECT  13.2 2.151 13.512 2.245 ;
     RECT  15.9 2.151 16.212 3.301 ;
     RECT  7.8 2.151 8.112 3.925 ;
     RECT  13.008 2.245 13.512 4.115 ;
     RECT  15.456 3.301 16.212 4.501 ;
     RECT  7.44 3.925 8.112 4.691 ;
     RECT  14.736 4.501 16.212 5.075 ;
     RECT  13.2 4.115 13.512 5.557 ;
     RECT  14.736 5.075 14.76 5.557 ;
     RECT  7.8 4.691 8.112 5.605 ;
     RECT  13.2 5.557 14.76 6.277 ;
     RECT  7.8 5.605 8.568 6.661 ;
     RECT  7.68 6.661 8.568 6.805 ;
     RECT  7.68 6.805 9.24 6.851 ;
     RECT  12.864 6.277 14.76 6.899 ;
     RECT  12.864 6.899 14.712 7.043 ;
     RECT  12.864 7.043 14.088 7.189 ;
     RECT  2.4 2.151 2.712 7.525 ;
     RECT  10.5 2.151 10.812 7.621 ;
     RECT  7.68 6.851 8.112 7.667 ;
     RECT  2.4 7.525 3.24 7.715 ;
     RECT  9.216 6.851 9.24 8.101 ;
     RECT  10.5 7.621 11.112 8.101 ;
     RECT  9.216 8.101 11.112 8.147 ;
     RECT  12.816 7.189 14.088 8.149 ;
     RECT  12.816 8.149 14.856 8.195 ;
     RECT  9.648 8.147 11.112 9.011 ;
     RECT  13.2 8.195 14.856 9.493 ;
     RECT  13.104 9.493 14.856 9.539 ;
     RECT  17.856 2.151 18.912 9.637 ;
     RECT  14.832 9.539 14.856 9.731 ;
     RECT  17.712 9.637 18.912 10.165 ;
     RECT  10.5 9.011 11.112 10.501 ;
     RECT  15.9 5.075 16.212 10.549 ;
     RECT  17.712 10.165 19.8 10.549 ;
     RECT  13.104 9.539 13.512 10.739 ;
     RECT  15.9 10.549 19.8 10.835 ;
     RECT  17.856 10.835 19.8 10.931 ;
     RECT  18 10.931 19.8 11.219 ;
     RECT  7.8 7.667 8.112 11.317 ;
     RECT  18.48 11.219 19.8 11.317 ;
     RECT  9.936 10.501 11.112 11.699 ;
     RECT  15.9 10.835 16.212 11.941 ;
     RECT  7.8 11.317 8.568 12.563 ;
     RECT  15.36 11.941 16.212 12.995 ;
     RECT  7.8 12.563 8.112 14.197 ;
     RECT  13.2 10.739 13.512 14.245 ;
     RECT  15.9 12.995 16.212 14.629 ;
     RECT  12.384 14.245 13.512 14.677 ;
     RECT  10.5 11.699 11.112 14.773 ;
     RECT  12.384 14.677 13.752 14.773 ;
     RECT  2.4 7.715 2.712 15.301 ;
     RECT  21.3 2.151 21.612 15.349 ;
     RECT  18.48 11.317 19.848 15.395 ;
     RECT  10.5 14.773 13.752 15.443 ;
     RECT  15.216 14.629 16.212 15.443 ;
     RECT  10.5 15.443 13.512 16.019 ;
     RECT  18.6 15.395 19.848 16.019 ;
     RECT  21.12 15.349 21.612 16.019 ;
     RECT  7.104 14.197 8.112 16.021 ;
     RECT  2.4 15.301 3.096 16.163 ;
     RECT  7.008 16.021 8.112 16.261 ;
     RECT  7.008 16.261 8.28 17.075 ;
     RECT  15.9 15.443 16.212 17.077 ;
     RECT  7.008 17.075 8.112 17.123 ;
     RECT  10.5 16.019 11.448 17.123 ;
     RECT  12.864 16.019 13.512 17.461 ;
     RECT  15.36 17.077 16.212 18.275 ;
     RECT  12.864 17.461 13.608 18.419 ;
     RECT  9.504 17.605 9.528 18.851 ;
     RECT  12.864 18.419 13.512 19.283 ;
     RECT  2.4 16.163 2.712 19.449 ;
     RECT  5.1 2.151 5.412 19.449 ;
     RECT  7.8 17.123 8.112 19.449 ;
     RECT  10.5 17.123 10.812 19.449 ;
     RECT  13.2 19.283 13.512 19.449 ;
     RECT  15.9 18.275 16.212 19.449 ;
     RECT  18.6 16.019 18.912 19.449 ;
     RECT  21.3 16.019 21.612 19.449 ;
     RECT  2.4 19.449 2.52 19.463 ;
     RECT  5.1 19.449 5.22 19.463 ;
     RECT  7.8 19.449 7.92 19.463 ;
     RECT  10.5 19.449 10.62 19.463 ;
     RECT  13.2 19.449 13.32 19.463 ;
     RECT  15.9 19.449 16.02 19.463 ;
     RECT  18.6 19.449 18.72 19.463 ;
     RECT  21.3 19.449 21.42 19.463 ;
  END
END qkd_landsh_36
END LIBRARY
